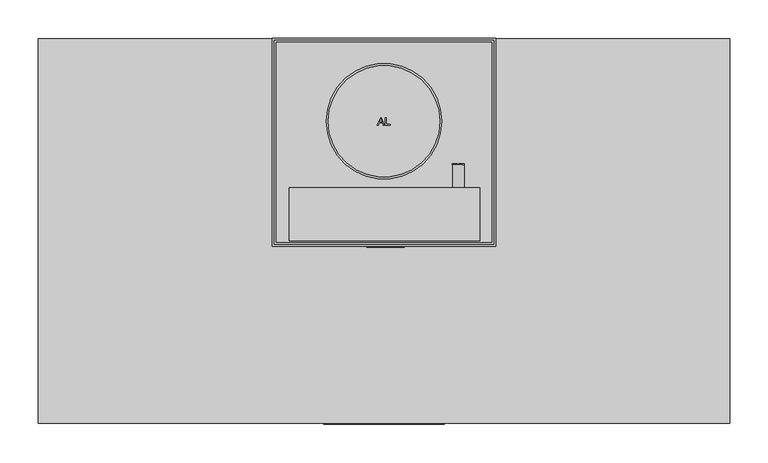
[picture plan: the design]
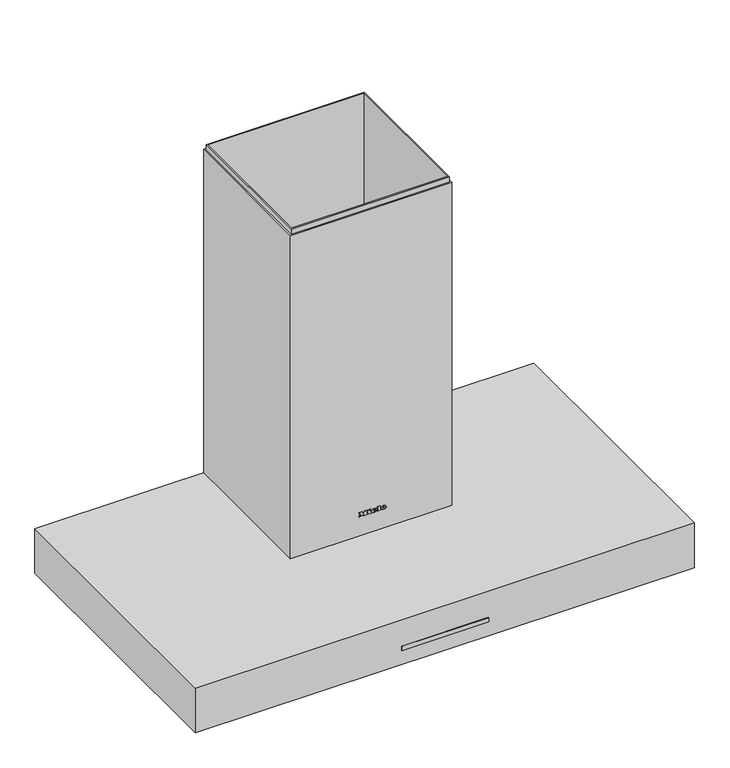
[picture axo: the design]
"""IFC4 building model written with IfcOpenShell, lengths in millimetres: proxy geometry."""

import ifcopenshell
import ifcopenshell.guid

model = None  # the IFC model being written
_history = None  # IfcOwnerHistory: only IFC2X3 demands one
_inside = {}  # id of a spatial element -> (the spatial element, [elements in it])
_under = {}  # id of a project, library or spatial element -> (it, [spatial elements below it])
_declared = {}  # id of a project -> (the project, [libraries it declares])
_typed = {}  # id of a type object -> (the type object, [elements of that type])
_made_of = {}  # id of a material, layer set ... -> (it, [elements and type objects made of it])


def new_model(schema):
    """Start an empty IFC model of exactly this schema.

    Asked for "IFC4X3", IfcOpenShell would pick the latest addendum, in which some entities
    have other attributes; the version numbers below select the first issue.
    IFC2X3 requires an IfcOwnerHistory on every rooted entity: one is made here for all.
    """
    global model, _history
    if schema == "IFC4X3":
        model = ifcopenshell.file(schema_version=(4, 3, 0, 0))
    else:
        model = ifcopenshell.file(schema=schema)
    _inside.clear()
    _under.clear()
    _declared.clear()
    _typed.clear()
    _made_of.clear()
    _history = None
    if model.schema == "IFC2X3":
        org = make("IfcOrganization", Name="unknown")
        user = make(
            "IfcPersonAndOrganization",
            ThePerson=make("IfcPerson", FamilyName="unknown"),
            TheOrganization=org,
        )
        app = make(
            "IfcApplication",
            ApplicationDeveloper=org,
            Version="unknown",
            ApplicationFullName="unknown",
            ApplicationIdentifier="unknown",
        )
        _history = make(
            "IfcOwnerHistory",
            OwningUser=user,
            OwningApplication=app,
            ChangeAction="ADDED",
            CreationDate=0,
        )
    return model


def make(cls, **values):
    """One entity of the class cls with the attributes given. An attribute that is None is left unset."""
    return model.create_entity(
        cls, **{name: value for name, value in values.items() if value is not None}
    )


def rooted(cls, **values):
    """An entity with a GlobalId (a new one), such as an element, a storey or a relation."""
    return make(cls, GlobalId=ifcopenshell.guid.new(), OwnerHistory=_history, **values)


def si_unit(unit_type, name, prefix=None):
    """IfcSIUnit, for example si_unit("LENGTHUNIT", "METRE", prefix="MILLI")."""
    return make("IfcSIUnit", UnitType=unit_type, Prefix=prefix, Name=name)


def assignment(units):
    """IfcUnitAssignment: the units of a project."""
    return None if units is None else make("IfcUnitAssignment", Units=units)


def point(xyz):
    """IfcCartesianPoint."""
    return None if xyz is None else make("IfcCartesianPoint", Coordinates=xyz)


def direction(xyz):
    """IfcDirection."""
    return None if xyz is None else make("IfcDirection", DirectionRatios=xyz)


def frame(location, z_axis=None, x_axis=None):
    """IfcAxis2Placement3D, a coordinate frame: its origin and axes. An axis left out is left unset."""
    return make(
        "IfcAxis2Placement3D",
        Location=point(location),
        Axis=direction(z_axis),
        RefDirection=direction(x_axis),
    )


def frame_2d(location, x_axis=None):
    """IfcAxis2Placement2D, a coordinate frame in the plane: its origin and x axis."""
    return make(
        "IfcAxis2Placement2D", Location=point(location), RefDirection=direction(x_axis)
    )


def origin():
    """The frame at (0, 0, 0) with its axes left unset."""
    return frame((0.0, 0.0, 0.0))


def place(relative_to, where):
    """IfcLocalPlacement: puts the frame where relative to a parent placement (None: the world)."""
    return make(
        "IfcLocalPlacement", PlacementRelTo=relative_to, RelativePlacement=where
    )


def context(
    kind, dimensions, precision=None, world=None, true_north=None, identifier=None
):
    """IfcGeometricRepresentationContext, for example the 3D "Model" context."""
    return make(
        "IfcGeometricRepresentationContext",
        ContextIdentifier=identifier,
        ContextType=kind,
        CoordinateSpaceDimension=dimensions,
        Precision=precision,
        WorldCoordinateSystem=world,
        TrueNorth=true_north,
    )


def project(units=None, contexts=None):
    """IfcProject with its units and contexts."""
    return rooted(
        "IfcProject",
        Name="project",
        RepresentationContexts=contexts,
        UnitsInContext=assignment(units),
    )


def spatial(cls, under=None, at=None, **own):
    """A site, building, storey or space (cls), placed at a placement, below another one or the project."""
    s = rooted(cls, ObjectPlacement=at, **own)
    if under is not None:
        _under.setdefault(under.id(), (under, []))[1].append(s)
    return s


def polyline(points):
    """IfcPolyline through the points."""
    return make("IfcPolyline", Points=[point(p) for p in points])


def circle_curve(where, radius):
    """IfcCircle in the frame where."""
    return make("IfcCircle", Position=where, Radius=radius)


def ellipse_curve(where, semi_axis1, semi_axis2):
    """IfcEllipse in the frame where."""
    return make(
        "IfcEllipse", Position=where, SemiAxis1=semi_axis1, SemiAxis2=semi_axis2
    )


def trimmed(basis, trim1, trim2, sense, master):
    """IfcTrimmedCurve: the piece of a basis curve between two trims."""
    return make(
        "IfcTrimmedCurve",
        BasisCurve=basis,
        Trim1=trim1,
        Trim2=trim2,
        SenseAgreement=sense,
        MasterRepresentation=master,
    )


def segment(curve, same_sense, transition):
    """IfcCompositeCurveSegment."""
    return make(
        "IfcCompositeCurveSegment",
        Transition=transition,
        SameSense=same_sense,
        ParentCurve=curve,
    )


def composite_curve(segments, self_intersect=None):
    """IfcCompositeCurve: segments joined end to end."""
    return make("IfcCompositeCurve", Segments=segments, SelfIntersect=self_intersect)


def outline(outer, holes=None, kind="AREA"):
    """IfcArbitraryClosedProfileDef: a profile drawn as a closed curve; with holes, ...WithVoids."""
    if holes is None:
        return make("IfcArbitraryClosedProfileDef", ProfileType=kind, OuterCurve=outer)
    return make(
        "IfcArbitraryProfileDefWithVoids",
        ProfileType=kind,
        OuterCurve=outer,
        InnerCurves=holes,
    )


def extrude(swept, where, along, depth):
    """IfcExtrudedAreaSolid: the profile swept, set in the frame where, extruded along a direction by depth."""
    return make(
        "IfcExtrudedAreaSolid",
        SweptArea=swept,
        Position=where,
        ExtrudedDirection=direction(along),
        Depth=depth,
    )


def faces_of(points, faces, orient=None, outer=None):
    """IfcFace entities. A face is a list of loops; a loop is a list of indices into points, from 0.

    orient and outer hold one flag for each loop. By default every Orientation is true, the
    first loop of a face is its IfcFaceOuterBound and the others are IfcFaceBound.
    """
    made = []
    for i, loops in enumerate(faces):
        bounds = []
        for j, loop in enumerate(loops):
            is_outer = j == 0 if outer is None else outer[i][j]
            bounds.append(
                make(
                    "IfcFaceOuterBound" if is_outer else "IfcFaceBound",
                    Bound=make("IfcPolyLoop", Polygon=[points[k] for k in loop]),
                    Orientation=True if orient is None else orient[i][j],
                )
            )
        made.append(make("IfcFace", Bounds=bounds))
    return made


def faceted_brep(points, faces, orient=None, outer=None, voids=None):
    """IfcFacetedBrep: a solid bounded by flat faces; with voids (closed shells), ...WithVoids."""
    shared = [point(p) for p in points]
    hull = make("IfcClosedShell", CfsFaces=faces_of(shared, faces, orient, outer))
    if voids is None:
        return make("IfcFacetedBrep", Outer=hull)
    return make(
        "IfcFacetedBrepWithVoids",
        Outer=hull,
        Voids=[
            make(cls, CfsFaces=faces_of(shared, fs, o, b)) for cls, fs, o, b in voids
        ],
    )


def shape(context_of_items, identifier, shape_type, items):
    """IfcShapeRepresentation: the items that make up one representation, for example the "Body"."""
    return make(
        "IfcShapeRepresentation",
        ContextOfItems=context_of_items,
        RepresentationIdentifier=identifier,
        RepresentationType=shape_type,
        Items=items,
    )


def source(mapping_origin, context_of_items, identifier, shape_type, items):
    """IfcRepresentationMap: a shape defined once, which mapped items show again and again."""
    return make(
        "IfcRepresentationMap",
        MappingOrigin=mapping_origin,
        MappedRepresentation=shape(context_of_items, identifier, shape_type, items),
    )


def transform(
    local_origin,
    x_axis=None,
    y_axis=None,
    z_axis=None,
    scale=None,
    scale2=None,
    scale3=None,
    uniform=True,
):
    """IfcCartesianTransformationOperator3D, or its non-uniform kind. x_axis, y_axis, z_axis: its Axis1, 2, 3."""
    if uniform:
        return make(
            "IfcCartesianTransformationOperator3D",
            Axis1=direction(x_axis),
            Axis2=direction(y_axis),
            LocalOrigin=point(local_origin),
            Scale=scale,
            Axis3=direction(z_axis),
        )
    return make(
        "IfcCartesianTransformationOperator3DnonUniform",
        Axis1=direction(x_axis),
        Axis2=direction(y_axis),
        LocalOrigin=point(local_origin),
        Scale=scale,
        Axis3=direction(z_axis),
        Scale2=scale2,
        Scale3=scale3,
    )


def mapped(mapping_source, mapping_target):
    """IfcMappedItem: shows the shape of a source again, moved by a transform."""
    return make(
        "IfcMappedItem", MappingSource=mapping_source, MappingTarget=mapping_target
    )


def made_of(thing, what):
    """Note that an element or type object is made of a material, layer set ...; save() writes the relation."""
    if what is not None:
        _made_of.setdefault(what.id(), (what, []))[1].append(thing)
    return thing


def element(
    cls,
    number,
    at=None,
    inside=None,
    cuts=None,
    type_object=None,
    material=None,
    context=None,
    identifier="Body",
    shape_type=None,
    held_by="IfcProductDefinitionShape",
    body=None,
    shapes=None,
    **own,
):
    """One element of the class cls, such as IfcWall. Its Tag is "e" and its number.

    at: its placement. inside: the storey or other place that contains it. cuts: it is an
    opening in that element (IfcRelVoidsElement). A single representation is given by context,
    identifier, shape_type and body (its items); several are given by shapes. held_by: the class
    of the entity that holds the representations. save() writes the other relations.
    """
    e = rooted(cls, Tag="e%d" % number, ObjectPlacement=at, **own)
    if body is not None:
        shapes = [shape(context, identifier, shape_type, body)]
    if shapes is not None:
        e.Representation = make(held_by, Representations=shapes)
    if inside is not None:
        _inside.setdefault(inside.id(), (inside, []))[1].append(e)
    if cuts is not None:
        rooted(
            "IfcRelVoidsElement", RelatingBuildingElement=cuts, RelatedOpeningElement=e
        )
    if type_object is not None:
        _typed.setdefault(type_object.id(), (type_object, []))[1].append(e)
    return made_of(e, material)


def aggregate(whole, parts):
    """IfcRelAggregates: a whole, such as a stair, and the parts it consists of."""
    return rooted("IfcRelAggregates", RelatingObject=whole, RelatedObjects=parts)


def save(model, path):
    """Write the relations noted so far, then the file.

    IfcRelAggregates (storeys below a building ...), IfcRelContainedInSpatialStructure (elements
    in a storey), IfcRelDefinesByType, IfcRelAssociatesMaterial and IfcRelDeclares: one each for
    every whole, place, type object, material and project.
    """
    for whole, parts in _under.values():
        aggregate(whole, parts)
    for where, things in _inside.values():
        rooted(
            "IfcRelContainedInSpatialStructure",
            RelatedElements=things,
            RelatingStructure=where,
        )
    for kind, things in _typed.values():
        rooted("IfcRelDefinesByType", RelatedObjects=things, RelatingType=kind)
    for what, things in _made_of.values():
        rooted("IfcRelAssociatesMaterial", RelatedObjects=things, RelatingMaterial=what)
    for by, libraries in _declared.values():
        rooted("IfcRelDeclares", RelatingContext=by, RelatedDefinitions=libraries)
    model.write(path)


def plane_surface(at):
    """IfcPlane: the flat surface through the origin of the frame at, square to its z axis."""
    return make("IfcPlane", Position=at)


def cylinder_surface(at, radius):
    """IfcCylindricalSurface: all points at the distance radius from the z axis of the frame at."""
    return make("IfcCylindricalSurface", Position=at, Radius=radius)


def revolved_surface(curve, axis_point, axis_direction):
    """IfcSurfaceOfRevolution: the curve turned about the line through axis_point along axis_direction."""
    return make(
        "IfcSurfaceOfRevolution",
        SweptCurve=make("IfcArbitraryOpenProfileDef", ProfileType="CURVE", Curve=curve),
        AxisPosition=make("IfcAxis1Placement", Location=point(axis_point), Axis=direction(axis_direction)),
    )


def extruded_surface(curve, direction_of_extrusion, depth):
    """IfcSurfaceOfLinearExtrusion: the curve pushed along a direction by depth."""
    return make(
        "IfcSurfaceOfLinearExtrusion",
        SweptCurve=make("IfcArbitraryOpenProfileDef", ProfileType="CURVE", Curve=curve),
        ExtrudedDirection=direction(direction_of_extrusion),
        Depth=depth,
    )


def advanced_brep(points, edges, surfaces, faces):
    """IfcAdvancedBrep: a solid bounded by faces that lie on surfaces and meet in shared edges.

    An edge is (start, end): straight between two places in points (the first is 0);
    or (start, end, curve); or (start, end, curve, False) where it runs against its curve.
    A face is (place in surfaces, loops), or (place, loops, False) where it looks against
    its surface's normal. A loop lists edges by number (the first is 1), with a minus sign
    where the edge is run from its end to its start. The first loop is the outer one.
    """
    corners = [point(p) for p in points]
    vertices = [make("IfcVertexPoint", VertexGeometry=c) for c in corners]
    made = []
    for start, end, *more in edges:
        made.append(
            make(
                "IfcEdgeCurve",
                EdgeStart=vertices[start],
                EdgeEnd=vertices[end],
                EdgeGeometry=more[0] if more else make("IfcPolyline", Points=[corners[start], corners[end]]),
                SameSense=more[1] if len(more) > 1 else True,
            )
        )
    hull = []
    for where, loops, *sense in faces:
        bounds = []
        for j, loop in enumerate(loops):
            ring = [make("IfcOrientedEdge", EdgeElement=made[abs(k) - 1], Orientation=k > 0) for k in loop]
            bounds.append(
                make(
                    "IfcFaceOuterBound" if j == 0 else "IfcFaceBound",
                    Bound=make("IfcEdgeLoop", EdgeList=ring),
                    Orientation=True,
                )
            )
        hull.append(make("IfcAdvancedFace", Bounds=bounds, FaceSurface=surfaces[where], SameSense=sense[0] if sense else True))
    return make("IfcAdvancedBrep", Outer=make("IfcClosedShell", CfsFaces=hull))


def specialty_equipment_d0c3b859(model_context):
    return source(origin(), model_context, "Body", "SolidModel", [
        advanced_brep(
        [(-270.0, -20.971114, 2.6236572), (-270.0, -76.028886, 17.3763428), (-270.0, -48.5, 10.0), (-270.0, -22.9370789, 1.9081045), (-270.0, -74.6840869, 15.7736735), (-270.0, -48.8105829, 8.840889)],
        [
            (0, 1, circle_curve(frame((-270.0, -48.5, 10.0), z_axis=(0.0, 0.25881904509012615, 0.9659258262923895), x_axis=(0.0, -0.9659258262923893, 0.2588190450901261)), 28.5)),
            (1, 2),
            (2, 0),
            (1, 0, circle_curve(frame((-270.0, -48.5, 10.0), z_axis=(0.0, 0.25881904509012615, 0.9659258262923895), x_axis=(0.0, -0.9659258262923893, 0.2588190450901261)), 28.5)),
            (0, 3),
            (3, 4, circle_curve(frame((-270.0, -48.8105829, 8.840889), z_axis=(0.0, 0.25881904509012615, 0.9659258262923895), x_axis=(0.0, -0.9659258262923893, 0.2588190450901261)), 26.7862224)),
            (4, 1),
            (4, 3, circle_curve(frame((-270.0, -48.8105829, 8.840889), z_axis=(0.0, 0.25881904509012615, 0.9659258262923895), x_axis=(0.0, -0.9659258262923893, 0.2588190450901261)), 26.7862224)),
            (3, 5),
            (5, 4),
        ],
        [
            plane_surface(frame((-270.0, -48.5, 10.0), z_axis=(0.0, 0.25881904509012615, 0.9659258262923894), x_axis=(0.0, -0.9659258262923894, 0.25881904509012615))),
            revolved_surface(polyline([(-270.0, -76.028886, 17.3763428), (-270.0, -74.6840869, 15.7736735)]), (-270.0, -48.5, 10.0), (0.0, -0.2588190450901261, -0.9659258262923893)),
            plane_surface(frame((-270.0, -48.8105829, 8.840889), z_axis=(0.0, -0.25881904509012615, -0.9659258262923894), x_axis=(0.0, -0.9659258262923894, 0.25881904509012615))),
        ],
        [
            (0, [[1, 2, 3]]),
            (0, [[-2, 4, -3]]),
            (1, [[-1, 5, 6, 7]]),
            (1, [[-4, -7, 8, -5]]),
            (2, [[-6, 9, 10]]),
            (2, [[-8, -10, -9]]),
        ],
    ),
        advanced_brep(
        [(0.0, -20.971114, 2.6236572), (0.0, -76.028886, 17.3763428), (0.0, -48.5, 10.0), (0.0, -22.9370789, 1.9081045), (0.0, -74.6840869, 15.7736735), (0.0, -48.8105829, 8.840889)],
        [
            (0, 1, circle_curve(frame((0.0, -48.5, 10.0), z_axis=(0.0, 0.2588190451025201, 0.9659258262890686), x_axis=(0.0, -0.9659258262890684, 0.25881904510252)), 28.5)),
            (1, 2),
            (2, 0),
            (1, 0, circle_curve(frame((0.0, -48.5, 10.0), z_axis=(0.0, 0.2588190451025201, 0.9659258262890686), x_axis=(0.0, -0.9659258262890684, 0.25881904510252)), 28.5)),
            (0, 3),
            (3, 4, circle_curve(frame((0.0, -48.8105829, 8.840889), z_axis=(0.0, 0.2588190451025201, 0.9659258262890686), x_axis=(0.0, -0.9659258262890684, 0.25881904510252)), 26.7862224)),
            (4, 1),
            (4, 3, circle_curve(frame((0.0, -48.8105829, 8.840889), z_axis=(0.0, 0.2588190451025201, 0.9659258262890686), x_axis=(0.0, -0.9659258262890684, 0.25881904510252)), 26.7862224)),
            (3, 5),
            (5, 4),
        ],
        [
            plane_surface(frame((0.0, -48.5, 10.0), z_axis=(0.0, 0.2588190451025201, 0.9659258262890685), x_axis=(0.0, -0.9659258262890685, 0.2588190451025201))),
            revolved_surface(polyline([(0.0, -76.028886, 17.3763428), (0.0, -74.6840869, 15.7736735)]), (0.0, -48.5, 10.0), (0.0, -0.25881904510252, -0.9659258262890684)),
            plane_surface(frame((0.0, -48.8105829, 8.840889), z_axis=(0.0, -0.2588190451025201, -0.9659258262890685), x_axis=(0.0, -0.9659258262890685, 0.2588190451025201))),
        ],
        [
            (0, [[1, 2, 3]]),
            (0, [[-2, 4, -3]]),
            (1, [[-1, 5, 6, 7]]),
            (1, [[-4, -7, 8, -5]]),
            (2, [[-6, 9, 10]]),
            (2, [[-8, -10, -9]]),
        ],
    ),
        advanced_brep(
        [(270.0, -20.971114, 2.6236572), (270.0, -76.028886, 17.3763428), (270.0, -48.5, 10.0), (270.0, -22.9370789, 1.9081045), (270.0, -74.6840869, 15.7736735), (270.0, -48.8105829, 8.840889)],
        [
            (0, 1, circle_curve(frame((270.0, -48.5, 10.0), z_axis=(0.0, 0.2588190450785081, 0.9659258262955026), x_axis=(0.0, -0.9659258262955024, 0.25881904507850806)), 28.5)),
            (1, 2),
            (2, 0),
            (1, 0, circle_curve(frame((270.0, -48.5, 10.0), z_axis=(0.0, 0.2588190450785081, 0.9659258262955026), x_axis=(0.0, -0.9659258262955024, 0.25881904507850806)), 28.5)),
            (0, 3),
            (3, 4, circle_curve(frame((270.0, -48.8105829, 8.840889), z_axis=(0.0, 0.2588190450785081, 0.9659258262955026), x_axis=(0.0, -0.9659258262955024, 0.25881904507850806)), 26.7862224)),
            (4, 1),
            (4, 3, circle_curve(frame((270.0, -48.8105829, 8.840889), z_axis=(0.0, 0.2588190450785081, 0.9659258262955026), x_axis=(0.0, -0.9659258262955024, 0.25881904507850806)), 26.7862224)),
            (3, 5),
            (5, 4),
        ],
        [
            plane_surface(frame((270.0, -48.5, 10.0), z_axis=(0.0, 0.2588190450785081, 0.9659258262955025), x_axis=(0.0, -0.9659258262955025, 0.2588190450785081))),
            revolved_surface(polyline([(270.0, -76.028886, 17.3763428), (270.0, -74.6840869, 15.7736735)]), (270.0, -48.5, 10.0), (0.0, -0.25881904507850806, -0.9659258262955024)),
            plane_surface(frame((270.0, -48.8105829, 8.840889), z_axis=(0.0, -0.2588190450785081, -0.9659258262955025), x_axis=(0.0, -0.9659258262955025, 0.2588190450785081))),
        ],
        [
            (0, [[1, 2, 3]]),
            (0, [[-2, 4, -3]]),
            (1, [[-1, 5, 6, 7]]),
            (1, [[-4, -7, 8, -5]]),
            (2, [[-6, 9, 10]]),
            (2, [[-8, -10, -9]]),
        ],
    ),
        extrude(outline(polyline([(131.6666667, -106.0), (131.6666667, -464.0), (-131.6666667, -464.0), (-131.6666667, -106.0), (131.6666667, -106.0)])), frame((0.0, 0.0, 6.5), z_axis=(0.0, 0.0, 1.0), x_axis=(1.0, 0.0, 0.0)), (0.0, 0.0, 1.0), 6.0),
        extrude(outline(polyline([(140.6666667, -97.0), (140.6666667, -473.0), (-140.6666667, -473.0), (-140.6666667, -97.0), (140.6666667, -97.0)]), holes=[polyline([(131.6666667, -106.0), (-131.6666667, -106.0), (-131.6666667, -464.0), (131.6666667, -464.0), (131.6666667, -106.0)])]), frame((0.0, 0.0, 5.0), z_axis=(0.0, 0.0, 1.0), x_axis=(1.0, 0.0, 0.0)), (0.0, 0.0, 1.0), 9.0),
        extrude(outline(polyline([(149.6666667, -106.0), (413.0, -106.0), (413.0, -464.0), (149.6666667, -464.0), (149.6666667, -106.0)])), frame((0.0, 0.0, 6.5), z_axis=(0.0, 0.0, 1.0), x_axis=(1.0, 0.0, 0.0)), (0.0, 0.0, 1.0), 6.0),
        extrude(outline(polyline([(140.6666667, -97.0), (422.0, -97.0), (422.0, -473.0), (140.6666667, -473.0), (140.6666667, -97.0)]), holes=[polyline([(149.6666667, -106.0), (149.6666667, -464.0), (413.0, -464.0), (413.0, -106.0), (149.6666667, -106.0)])]), frame((0.0, 0.0, 5.0), z_axis=(0.0, 0.0, 1.0), x_axis=(1.0, 0.0, 0.0)), (0.0, 0.0, 1.0), 9.0),
        extrude(outline(polyline([(-149.6666667, -106.0), (-149.6666667, -464.0), (-413.0, -464.0), (-413.0, -106.0), (-149.6666667, -106.0)])), frame((0.0, 0.0, 6.5), z_axis=(0.0, 0.0, 1.0), x_axis=(1.0, 0.0, 0.0)), (0.0, 0.0, 1.0), 6.0),
        extrude(outline(polyline([(-140.6666667, -97.0), (-140.6666667, -473.0), (-422.0, -473.0), (-422.0, -97.0), (-140.6666667, -97.0)]), holes=[polyline([(-149.6666667, -106.0), (-413.0, -106.0), (-413.0, -464.0), (-149.6666667, -464.0), (-149.6666667, -106.0)])]), frame((0.0, 0.0, 5.0), z_axis=(0.0, 0.0, 1.0), x_axis=(1.0, 0.0, 0.0)), (0.0, 0.0, 1.0), 9.0),
        extrude(outline(polyline([(16.5, -421.0), (16.5, -464.0), (-16.5, -464.0), (-16.5, -421.0), (16.5, -421.0)]), holes=[polyline([(10.0, -427.5), (-10.0, -427.5), (-10.0, -436.5), (10.0, -436.5), (10.0, -427.5)])]), frame((0.0, 0.0, 5.0), z_axis=(0.0, 0.0, 1.0), x_axis=(1.0, 0.0, 0.0)), (0.0, 0.0, 1.0), 1.5),
        extrude(outline(polyline([(264.8333333, -421.0), (297.8333333, -421.0), (297.8333333, -464.0), (264.8333333, -464.0), (264.8333333, -421.0)]), holes=[polyline([(271.3333333, -427.5), (271.3333333, -436.5), (291.1047662, -436.5), (291.1047662, -427.5), (271.3333333, -427.5)])]), frame((0.0, 0.0, 5.0), z_axis=(0.0, 0.0, 1.0), x_axis=(1.0, 0.0, 0.0)), (0.0, 0.0, 1.0), 1.5),
        extrude(outline(polyline([(-264.8333333, -421.0), (-264.8333333, -464.0), (-297.8333333, -464.0), (-297.8333333, -421.0), (-264.8333333, -421.0)]), holes=[polyline([(-271.3333333, -427.5), (-291.3333333, -427.5), (-291.3333333, -436.5), (-271.3333333, -436.5), (-271.3333333, -427.5)])]), frame((0.0, 0.0, 5.0), z_axis=(0.0, 0.0, 1.0), x_axis=(1.0, 0.0, 0.0)), (0.0, 0.0, 1.0), 1.5),
        faceted_brep([(140.0, -5.0, 710.0), (-140.0, -5.0, 710.0), (-140.0, -5.0, 235.0), (140.0, -5.0, 235.0), (-140.0, -265.0, 710.0), (140.0, -265.0, 710.0), (140.0, -265.0, 235.0), (-140.0, -265.0, 235.0), (121.0, -265.0, 270.0), (121.0, -265.0, 370.0), (109.0, -265.0, 370.0), (109.0, -265.0, 270.0), (-121.0, -265.0, 370.0), (-121.0, -265.0, 270.0), (-109.0, -265.0, 270.0), (-109.0, -265.0, 370.0), (-86.0, -265.0, 370.0), (-97.5, -265.0, 370.0), (-97.5, -265.0, 270.0), (-86.0, -265.0, 270.0), (-63.0, -265.0, 370.0), (-74.5, -265.0, 370.0), (-74.5, -265.0, 270.0), (-63.0, -265.0, 270.0), (-40.0, -265.0, 370.0), (-51.5, -265.0, 370.0), (-51.5, -265.0, 270.0), (-40.0, -265.0, 270.0), (-17.0, -265.0, 370.0), (-28.5, -265.0, 370.0), (-28.5, -265.0, 270.0), (-17.0, -265.0, 270.0), (5.5, -265.0, 370.0), (-5.5, -265.0, 370.0), (-5.5, -265.0, 270.0), (5.5, -265.0, 270.0), (28.5, -265.0, 370.0), (17.0, -265.0, 370.0), (17.0, -265.0, 270.0), (28.5, -265.0, 270.0), (51.5, -265.0, 370.0), (40.0, -265.0, 370.0), (40.0, -265.0, 270.0), (51.5, -265.0, 270.0), (74.5, -265.0, 370.0), (63.0, -265.0, 370.0), (63.0, -265.0, 270.0), (74.5, -265.0, 270.0), (97.5, -265.0, 370.0), (86.0, -265.0, 370.0), (86.0, -265.0, 270.0), (97.5, -265.0, 270.0), (-142.5, -65.4, 270.0), (-140.0, -65.4, 270.0), (-140.0, -65.4, 370.0), (-142.5, -65.4, 370.0), (-140.0, -76.0, 370.0), (-142.5, -76.0, 370.0), (-140.0, -44.2, 270.0), (-142.5, -44.2, 270.0), (-142.5, -54.8, 270.0), (-140.0, -54.8, 270.0), (-140.0, -44.2, 370.0), (-142.5, -44.2, 370.0), (-140.0, -23.0, 270.0), (-142.5, -23.0, 270.0), (-142.5, -33.6, 270.0), (-140.0, -33.6, 270.0), (-140.0, -23.0, 370.0), (-142.5, -23.0, 370.0), (-121.0, -267.5, 370.0), (-109.0, -267.5, 370.0), (-109.0, -267.5, 270.0), (-86.0, -267.5, 370.0), (-97.5, -267.5, 370.0), (-63.0, -267.5, 370.0), (-74.5, -267.5, 370.0), (-40.0, -267.5, 370.0), (-51.5, -267.5, 370.0), (-17.0, -267.5, 370.0), (-28.5, -267.5, 370.0), (5.5, -267.5, 370.0), (-5.5, -267.5, 370.0), (28.5, -267.5, 370.0), (17.0, -267.5, 370.0), (51.5, -267.5, 370.0), (40.0, -267.5, 370.0), (74.5, -267.5, 370.0), (63.0, -267.5, 370.0), (97.5, -267.5, 370.0), (86.0, -267.5, 370.0), (-142.5, -267.5, 710.0), (142.5, -267.5, 710.0), (142.5, -2.5, 710.0), (-142.5, -2.5, 710.0), (-142.5, -267.5, 235.0), (-142.5, -2.5, 235.0), (142.5, -2.5, 235.0), (142.5, -267.5, 235.0), (-142.5, -247.0, 270.0), (-142.5, -236.4, 270.0), (-142.5, -236.4, 370.0), (-142.5, -247.0, 370.0), (-142.5, -225.8, 270.0), (-142.5, -215.2, 270.0), (-142.5, -215.2, 370.0), (-142.5, -225.8, 370.0), (-142.5, -204.6, 270.0), (-142.5, -194.0, 270.0), (-142.5, -194.0, 370.0), (-142.5, -204.6, 370.0), (-142.5, -183.4, 270.0), (-142.5, -172.8, 270.0), (-142.5, -172.8, 370.0), (-142.5, -183.4, 370.0), (-142.5, -162.2, 270.0), (-142.5, -151.6, 270.0), (-142.5, -151.6, 370.0), (-142.5, -162.2, 370.0), (-142.5, -141.0, 270.0), (-142.5, -129.0, 270.0), (-142.5, -129.0, 370.0), (-142.5, -141.0, 370.0), (-142.5, -118.4, 270.0), (-142.5, -107.8, 270.0), (-142.5, -107.8, 370.0), (-142.5, -118.4, 370.0), (-142.5, -97.2, 270.0), (-142.5, -86.6, 270.0), (-142.5, -86.6, 370.0), (-142.5, -97.2, 370.0), (-142.5, -76.0, 270.0), (-142.5, -54.8, 370.0), (-142.5, -33.6, 370.0), (-140.0, -236.4, 270.0), (-140.0, -247.0, 270.0), (-140.0, -247.0, 370.0), (-140.0, -236.4, 370.0), (-140.0, -215.2, 270.0), (-140.0, -225.8, 270.0), (-140.0, -225.8, 370.0), (-140.0, -215.2, 370.0), (-140.0, -194.0, 270.0), (-140.0, -204.6, 270.0), (-140.0, -204.6, 370.0), (-140.0, -194.0, 370.0), (-140.0, -172.8, 270.0), (-140.0, -183.4, 270.0), (-140.0, -183.4, 370.0), (-140.0, -172.8, 370.0), (-140.0, -151.6, 270.0), (-140.0, -162.2, 270.0), (-140.0, -162.2, 370.0), (-140.0, -151.6, 370.0), (-140.0, -129.0, 270.0), (-140.0, -141.0, 270.0), (-140.0, -141.0, 370.0), (-140.0, -129.0, 370.0), (-140.0, -107.8, 270.0), (-140.0, -118.4, 270.0), (-140.0, -118.4, 370.0), (-140.0, -107.8, 370.0), (-140.0, -86.6, 270.0), (-140.0, -97.2, 270.0), (-140.0, -97.2, 370.0), (-140.0, -86.6, 370.0), (-140.0, -76.0, 270.0), (-140.0, -54.8, 370.0), (-140.0, -33.6, 370.0), (140.0, -162.2, 370.0), (140.0, -162.2, 270.0), (140.0, -151.6, 270.0), (140.0, -151.6, 370.0), (140.0, -44.2, 270.0), (140.0, -44.2, 370.0), (140.0, -54.8, 370.0), (140.0, -54.8, 270.0), (140.0, -65.4, 270.0), (140.0, -65.4, 370.0), (140.0, -76.0, 370.0), (140.0, -76.0, 270.0), (140.0, -86.6, 270.0), (140.0, -86.6, 370.0), (140.0, -97.2, 370.0), (140.0, -97.2, 270.0), (140.0, -107.8, 270.0), (140.0, -107.8, 370.0), (140.0, -118.4, 370.0), (140.0, -118.4, 270.0), (140.0, -129.0, 270.0), (140.0, -129.0, 370.0), (140.0, -141.0, 370.0), (140.0, -141.0, 270.0), (140.0, -247.0, 370.0), (140.0, -247.0, 270.0), (140.0, -236.4, 270.0), (140.0, -236.4, 370.0), (140.0, -23.0, 270.0), (140.0, -23.0, 370.0), (140.0, -33.6, 370.0), (140.0, -33.6, 270.0), (140.0, -225.8, 370.0), (140.0, -225.8, 270.0), (140.0, -215.2, 270.0), (140.0, -215.2, 370.0), (140.0, -204.6, 370.0), (140.0, -204.6, 270.0), (140.0, -194.0, 270.0), (140.0, -194.0, 370.0), (140.0, -183.4, 370.0), (140.0, -183.4, 270.0), (140.0, -172.8, 270.0), (140.0, -172.8, 370.0), (142.5, -225.8, 270.0), (142.5, -225.8, 370.0), (142.5, -215.2, 370.0), (142.5, -215.2, 270.0), (142.5, -204.6, 270.0), (142.5, -204.6, 370.0), (142.5, -194.0, 370.0), (142.5, -194.0, 270.0), (142.5, -183.4, 270.0), (142.5, -183.4, 370.0), (142.5, -172.8, 370.0), (142.5, -172.8, 270.0), (142.5, -162.2, 270.0), (142.5, -162.2, 370.0), (142.5, -151.6, 370.0), (142.5, -151.6, 270.0), (142.5, -44.2, 370.0), (142.5, -44.2, 270.0), (142.5, -54.8, 270.0), (142.5, -54.8, 370.0), (142.5, -65.4, 370.0), (142.5, -65.4, 270.0), (142.5, -76.0, 270.0), (142.5, -76.0, 370.0), (142.5, -86.6, 370.0), (142.5, -86.6, 270.0), (142.5, -97.2, 270.0), (142.5, -97.2, 370.0), (142.5, -107.8, 370.0), (142.5, -107.8, 270.0), (142.5, -118.4, 270.0), (142.5, -118.4, 370.0), (142.5, -129.0, 370.0), (142.5, -129.0, 270.0), (142.5, -141.0, 270.0), (142.5, -141.0, 370.0), (142.5, -23.0, 370.0), (142.5, -23.0, 270.0), (142.5, -33.6, 270.0), (142.5, -33.6, 370.0), (142.5, -247.0, 270.0), (142.5, -247.0, 370.0), (142.5, -236.4, 370.0), (142.5, -236.4, 270.0), (-86.0, -267.5, 270.0), (-97.5, -267.5, 270.0), (-63.0, -267.5, 270.0), (-74.5, -267.5, 270.0), (-40.0, -267.5, 270.0), (-51.5, -267.5, 270.0), (-17.0, -267.5, 270.0), (-28.5, -267.5, 270.0), (5.5, -267.5, 270.0), (-5.5, -267.5, 270.0), (28.5, -267.5, 270.0), (17.0, -267.5, 270.0), (51.5, -267.5, 270.0), (40.0, -267.5, 270.0), (74.5, -267.5, 270.0), (63.0, -267.5, 270.0), (97.5, -267.5, 270.0), (86.0, -267.5, 270.0), (121.0, -267.5, 370.0), (121.0, -267.5, 270.0), (109.0, -267.5, 270.0), (109.0, -267.5, 370.0), (-121.0, -267.5, 270.0)], [[[0, 1, 2, 3]], [[4, 5, 6, 7], [8, 9, 10, 11], [12, 13, 14, 15], [16, 17, 18, 19], [20, 21, 22, 23], [24, 25, 26, 27], [28, 29, 30, 31], [32, 33, 34, 35], [36, 37, 38, 39], [40, 41, 42, 43], [44, 45, 46, 47], [48, 49, 50, 51]], [[52, 53, 54, 55]], [[55, 54, 56, 57]], [[58, 59, 60, 61]], [[59, 58, 62, 63]], [[64, 65, 66, 67]], [[65, 64, 68, 69]], [[70, 12, 15, 71]], [[71, 15, 14, 72]], [[16, 73, 74, 17]], [[20, 75, 76, 21]], [[24, 77, 78, 25]], [[28, 79, 80, 29]], [[32, 81, 82, 33]], [[36, 83, 84, 37]], [[40, 85, 86, 41]], [[44, 87, 88, 45]], [[48, 89, 90, 49]], [[91, 92, 93, 94], [0, 5, 4, 1]], [[95, 96, 97, 98], [3, 2, 7, 6]], [[91, 94, 96, 95], [99, 100, 101, 102], [103, 104, 105, 106], [107, 108, 109, 110], [111, 112, 113, 114], [115, 116, 117, 118], [119, 120, 121, 122], [123, 124, 125, 126], [127, 128, 129, 130], [131, 52, 55, 57], [60, 59, 63, 132], [66, 65, 69, 133]], [[1, 4, 7, 2], [134, 135, 136, 137], [138, 139, 140, 141], [142, 143, 144, 145], [146, 147, 148, 149], [150, 151, 152, 153], [154, 155, 156, 157], [158, 159, 160, 161], [162, 163, 164, 165], [53, 166, 56, 54], [58, 61, 167, 62], [64, 67, 168, 68]], [[5, 0, 3, 6], [169, 170, 171, 172], [173, 174, 175, 176], [177, 178, 179, 180], [181, 182, 183, 184], [185, 186, 187, 188], [189, 190, 191, 192], [193, 194, 195, 196], [197, 198, 199, 200], [201, 202, 203, 204], [205, 206, 207, 208], [209, 210, 211, 212]], [[93, 92, 98, 97], [213, 214, 215, 216], [217, 218, 219, 220], [221, 222, 223, 224], [225, 226, 227, 228], [229, 230, 231, 232], [233, 234, 235, 236], [237, 238, 239, 240], [241, 242, 243, 244], [245, 246, 247, 248], [249, 250, 251, 252], [253, 254, 255, 256]], [[92, 91, 95, 98], [74, 73, 257, 258], [76, 75, 259, 260], [78, 77, 261, 262], [80, 79, 263, 264], [82, 81, 265, 266], [84, 83, 267, 268], [86, 85, 269, 270], [88, 87, 271, 272], [90, 89, 273, 274], [275, 276, 277, 278], [279, 70, 71, 72]], [[94, 93, 97, 96]], [[8, 276, 275, 9]], [[12, 70, 279, 13]], [[253, 194, 193, 254]], [[249, 198, 197, 250]], [[194, 253, 256, 195]], [[195, 256, 255, 196]], [[254, 193, 196, 255]], [[198, 249, 252, 199]], [[199, 252, 251, 200]], [[250, 197, 200, 251]], [[213, 202, 201, 214]], [[202, 213, 216, 203]], [[203, 216, 215, 204]], [[214, 201, 204, 215]], [[217, 206, 205, 218]], [[206, 217, 220, 207]], [[207, 220, 219, 208]], [[218, 205, 208, 219]], [[221, 210, 209, 222]], [[210, 221, 224, 211]], [[211, 224, 223, 212]], [[222, 209, 212, 223]], [[225, 170, 169, 226]], [[170, 225, 228, 171]], [[171, 228, 227, 172]], [[226, 169, 172, 227]], [[229, 174, 173, 230]], [[174, 229, 232, 175]], [[175, 232, 231, 176]], [[230, 173, 176, 231]], [[233, 178, 177, 234]], [[178, 233, 236, 179]], [[179, 236, 235, 180]], [[234, 177, 180, 235]], [[237, 182, 181, 238]], [[182, 237, 240, 183]], [[183, 240, 239, 184]], [[238, 181, 184, 239]], [[241, 186, 185, 242]], [[186, 241, 244, 187]], [[187, 244, 243, 188]], [[242, 185, 188, 243]], [[245, 190, 189, 246]], [[190, 245, 248, 191]], [[191, 248, 247, 192]], [[246, 189, 192, 247]], [[134, 100, 99, 135]], [[100, 134, 137, 101]], [[101, 137, 136, 102]], [[135, 99, 102, 136]], [[138, 104, 103, 139]], [[104, 138, 141, 105]], [[105, 141, 140, 106]], [[139, 103, 106, 140]], [[142, 108, 107, 143]], [[108, 142, 145, 109]], [[109, 145, 144, 110]], [[143, 107, 110, 144]], [[146, 112, 111, 147]], [[112, 146, 149, 113]], [[113, 149, 148, 114]], [[147, 111, 114, 148]], [[150, 116, 115, 151]], [[116, 150, 153, 117]], [[117, 153, 152, 118]], [[151, 115, 118, 152]], [[154, 120, 119, 155]], [[120, 154, 157, 121]], [[121, 157, 156, 122]], [[155, 119, 122, 156]], [[158, 124, 123, 159]], [[124, 158, 161, 125]], [[125, 161, 160, 126]], [[159, 123, 126, 160]], [[162, 128, 127, 163]], [[128, 162, 165, 129]], [[129, 165, 164, 130]], [[163, 127, 130, 164]], [[53, 52, 131, 166]], [[166, 131, 57, 56]], [[63, 62, 167, 132]], [[61, 60, 132, 167]], [[69, 68, 168, 133]], [[67, 66, 133, 168]], [[13, 279, 72, 14]], [[276, 8, 11, 277]], [[277, 11, 10, 278]], [[9, 275, 278, 10]], [[73, 16, 19, 257]], [[257, 19, 18, 258]], [[17, 74, 258, 18]], [[75, 20, 23, 259]], [[259, 23, 22, 260]], [[21, 76, 260, 22]], [[77, 24, 27, 261]], [[261, 27, 26, 262]], [[25, 78, 262, 26]], [[79, 28, 31, 263]], [[263, 31, 30, 264]], [[29, 80, 264, 30]], [[81, 32, 35, 265]], [[265, 35, 34, 266]], [[33, 82, 266, 34]], [[83, 36, 39, 267]], [[267, 39, 38, 268]], [[37, 84, 268, 38]], [[85, 40, 43, 269]], [[269, 43, 42, 270]], [[41, 86, 270, 42]], [[87, 44, 47, 271]], [[271, 47, 46, 272]], [[45, 88, 272, 46]], [[89, 48, 51, 273]], [[273, 51, 50, 274]], [[49, 90, 274, 50]]]),
        extrude(outline(polyline([(145.0, 0.0), (145.0, -270.0), (-145.0, -270.0), (-145.0, 0.0), (145.0, 0.0)]), holes=[polyline([(-142.5, -2.5), (-142.5, -267.5), (142.5, -267.5), (142.5, -2.5), (-142.5, -2.5)])]), frame((0.0, 0.0, 85.0), z_axis=(0.0, 0.0, 1.0), x_axis=(1.0, 0.0, 0.0)), (0.0, 0.0, 1.0), 615.0),
        advanced_brep(
        [(21.104, -271.0, 123.896), (21.104, -271.0, 124.704), (26.456, -271.0, 124.704), (17.144, -271.0, 124.704), (19.344, -271.0, 122.0), (26.32, -271.0, 123.896), (23.904, -271.0, 123.896), (22.0, -271.0, 123.0), (21.104, -271.0, 125.728), (21.104, -271.0, 126.6), (22.472, -271.0, 126.6), (22.472, -271.0, 125.728), (21.104, -270.0, 123.896), (22.0, -270.0, 123.0), (23.904, -270.0, 123.896), (26.32, -270.0, 123.896), (19.344, -270.0, 122.0), (17.144, -270.0, 124.704), (26.456, -270.0, 124.704), (21.104, -270.0, 124.704), (21.104, -270.0, 125.728), (22.472, -270.0, 125.728), (22.472, -270.0, 126.6), (21.104, -270.0, 126.6)],
        [
            (0, 1),
            (1, 2),
            (2, 3, ellipse_curve(frame((21.8, -271.0, 124.704), z_axis=(0.0, -1.0, -1.2192856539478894e-11), x_axis=(-1.0, 0.0, 0.0)), 4.656, 3.848)),
            (3, 4, circle_curve(frame((20.2400436, -271.0, 124.976), z_axis=(0.0, -1.0, -1.2192856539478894e-11), x_axis=(0.0, 1.2192856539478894e-11, -1.0)), 3.1079688)),
            (4, 5, circle_curve(frame((21.7067936, -271.0, 127.088), z_axis=(0.0, -1.0, -1.2192856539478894e-11), x_axis=(0.0, 1.2192856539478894e-11, -1.0)), 5.6098607)),
            (5, 6),
            (6, 7, circle_curve(frame((22.3910588, -271.0, 124.64), z_axis=(0.0, 1.0, 1.2192856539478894e-11), x_axis=(0.0, 1.2192856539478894e-11, -1.0)), 1.6859795)),
            (7, 0, circle_curve(frame((22.0, -271.0, 123.896), z_axis=(0.0, 1.0, 1.2192856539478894e-11), x_axis=(0.0, 1.2192856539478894e-11, -1.0)), 0.896)),
            (8, 9),
            (9, 10, circle_curve(frame((21.788, -271.0, 126.6), z_axis=(0.0, 1.0, 1.2192856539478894e-11), x_axis=(0.0, 1.2192856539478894e-11, -1.0)), 0.684)),
            (10, 11),
            (11, 8),
            (12, 13, circle_curve(frame((22.0, -270.0, 123.896), z_axis=(0.0, -1.0, -1.2192856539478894e-11), x_axis=(0.0, 1.2192856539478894e-11, -1.0)), 0.896)),
            (13, 14, circle_curve(frame((22.3910588, -270.0, 124.64), z_axis=(0.0, -1.0, -1.2192856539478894e-11), x_axis=(0.0, 1.2192856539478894e-11, -1.0)), 1.6859795)),
            (14, 15),
            (15, 16, circle_curve(frame((21.7067936, -270.0, 127.088), z_axis=(0.0, 1.0, 1.2192856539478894e-11), x_axis=(0.0, 1.2192856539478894e-11, -1.0)), 5.6098607)),
            (16, 17, circle_curve(frame((20.2400436, -270.0, 124.976), z_axis=(0.0, 1.0, 1.2192856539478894e-11), x_axis=(0.0, 1.2192856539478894e-11, -1.0)), 3.1079688)),
            (17, 18, ellipse_curve(frame((21.8, -270.0, 124.704), z_axis=(0.0, 1.0, 1.2192856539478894e-11), x_axis=(-1.0, 0.0, 0.0)), 4.656, 3.848)),
            (18, 19),
            (19, 12),
            (20, 21),
            (21, 22),
            (22, 23, circle_curve(frame((21.788, -270.0, 126.6), z_axis=(0.0, -1.0, -1.2192856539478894e-11), x_axis=(0.0, 1.2192856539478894e-11, -1.0)), 0.684)),
            (23, 20),
            (0, 12),
            (19, 1),
            (18, 2),
            (5, 15),
            (14, 6),
            (17, 3),
            (13, 7),
            (16, 4),
            (8, 20),
            (23, 9),
            (22, 10),
            (21, 11),
        ],
        [
            plane_surface(frame((21.104, -271.0, 124.704), z_axis=(0.0, -1.0, -1.2192856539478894e-11), x_axis=(0.0, -1.2192856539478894e-11, 1.0))),
            plane_surface(frame((21.104, -270.0, 124.704), z_axis=(0.0, 1.0, 1.2192856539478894e-11), x_axis=(0.0, 1.2192856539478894e-11, -1.0))),
            plane_surface(frame((21.104, -271.0, 123.896), z_axis=(1.0, 0.0, 0.0), x_axis=(0.0, 1.0, 1.2192856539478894e-11))),
            plane_surface(frame((21.104, -271.0, 124.704), z_axis=(0.0, 1.2192856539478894e-11, -1.0), x_axis=(0.0, 1.0, 1.2192856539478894e-11))),
            plane_surface(frame((26.32, -271.0, 123.896), z_axis=(0.0, -1.2192856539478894e-11, 1.0), x_axis=(0.0, 1.0, 1.2192856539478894e-11))),
            extruded_surface(trimmed(ellipse_curve(frame((21.8, -269.0, 124.704), z_axis=(0.0, -1.0, -1.2192856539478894e-11), x_axis=(-1.0, 0.0, 0.0)), 4.656, 3.848), [point((26.456, -269.0, 124.704))], [point((17.144, -269.0, 124.704))], True, "CARTESIAN"), (0.0, -1.0, 0.0), 1.0),
            revolved_surface(polyline([(22.3910588, -269.9999999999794, 122.9540205), (22.3910588, -270.99999999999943, 122.9540204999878)]), (22.3910588, -270.0, 124.64), (0.0, 1.0, 1.2192856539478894e-11)),
            revolved_surface(polyline([(22.0, -269.9999999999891, 123.0), (22.0, -271.0, 122.9999999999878)]), (22.0, -270.0, 123.896), (0.0, 1.0, 1.2192856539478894e-11)),
            cylinder_surface(frame((20.2400436, -270.0, 124.976), z_axis=(0.0, -1.0, -1.2192856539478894e-11), x_axis=(0.0, 1.2192856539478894e-11, -1.0)), 3.1079688),
            cylinder_surface(frame((21.7067936, -270.0, 127.088), z_axis=(0.0, -1.0, -1.2192856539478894e-11), x_axis=(0.0, 1.2192856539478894e-11, -1.0)), 5.6098607),
            plane_surface(frame((21.104, -271.0, 125.728), z_axis=(1.0, 0.0, 0.0), x_axis=(0.0, 1.0, 1.2192856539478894e-11))),
            revolved_surface(polyline([(21.788, -269.99999999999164, 125.916), (21.788, -270.99999999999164, 125.9159999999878)]), (21.788, -270.0, 126.6), (0.0, 1.0, 1.2192856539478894e-11)),
            plane_surface(frame((22.472, -271.0, 126.6), z_axis=(-1.0, 0.0, 0.0), x_axis=(0.0, 1.0, 1.2192856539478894e-11))),
            plane_surface(frame((22.472, -271.0, 125.728), z_axis=(0.0, -1.2192856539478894e-11, 1.0), x_axis=(0.0, 1.0, 1.2192856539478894e-11))),
        ],
        [
            (0, [[1, 2, 3, 4, 5, 6, 7, 8], [9, 10, 11, 12]]),
            (1, [[13, 14, 15, 16, 17, 18, 19, 20], [21, 22, 23, 24]]),
            (2, [[-1, 25, -20, 26]]),
            (3, [[-2, -26, -19, 27]]),
            (4, [[-6, 28, -15, 29]]),
            (5, [[-3, -27, -18, 30]]),
            (6, [[-7, -29, -14, 31]]),
            (7, [[-8, -31, -13, -25]]),
            (8, [[-4, -30, -17, 32]]),
            (9, [[-5, -32, -16, -28]]),
            (10, [[-9, 33, -24, 34]]),
            (11, [[-10, -34, -23, 35]]),
            (12, [[-11, -35, -22, 36]]),
            (13, [[-12, -36, -21, -33]]),
        ],
    ),
        advanced_brep(
        [(4.408, -271.0, 123.896), (4.408, -271.0, 124.704), (9.76, -271.0, 124.704), (0.448, -271.0, 124.704), (2.648, -271.0, 122.0), (9.624, -271.0, 123.896), (7.208, -271.0, 123.896), (5.304, -271.0, 123.0), (4.408, -271.0, 125.728), (4.408, -271.0, 126.6), (5.776, -271.0, 126.6), (5.776, -271.0, 125.728), (4.408, -270.0, 123.896), (5.304, -270.0, 123.0), (7.208, -270.0, 123.896), (9.624, -270.0, 123.896), (2.648, -270.0, 122.0), (0.448, -270.0, 124.704), (9.76, -270.0, 124.704), (4.408, -270.0, 124.704), (4.408, -270.0, 125.728), (5.776, -270.0, 125.728), (5.776, -270.0, 126.6), (4.408, -270.0, 126.6)],
        [
            (0, 1),
            (1, 2),
            (2, 3, ellipse_curve(frame((5.104, -271.0, 124.704), z_axis=(0.0, -1.0, -1.2192856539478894e-11), x_axis=(-1.0, 0.0, 0.0)), 4.656, 3.848)),
            (3, 4, circle_curve(frame((3.5440436, -271.0, 124.976), z_axis=(0.0, -1.0, -1.2192856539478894e-11), x_axis=(0.0, 1.2192856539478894e-11, -1.0)), 3.1079688)),
            (4, 5, circle_curve(frame((5.0107936, -271.0, 127.088), z_axis=(0.0, -1.0, -1.2192856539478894e-11), x_axis=(0.0, 1.2192856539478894e-11, -1.0)), 5.6098607)),
            (5, 6),
            (6, 7, circle_curve(frame((5.6950588, -271.0, 124.64), z_axis=(0.0, 1.0, 1.2192856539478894e-11), x_axis=(0.0, 1.2192856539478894e-11, -1.0)), 1.6859795)),
            (7, 0, circle_curve(frame((5.304, -271.0, 123.896), z_axis=(0.0, 1.0, 1.2192856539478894e-11), x_axis=(0.0, 1.2192856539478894e-11, -1.0)), 0.896)),
            (8, 9),
            (9, 10, circle_curve(frame((5.092, -271.0, 126.6), z_axis=(0.0, 1.0, 1.2192856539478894e-11), x_axis=(0.0, 1.2192856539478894e-11, -1.0)), 0.684)),
            (10, 11),
            (11, 8),
            (12, 13, circle_curve(frame((5.304, -270.0, 123.896), z_axis=(0.0, -1.0, -1.2192856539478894e-11), x_axis=(0.0, 1.2192856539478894e-11, -1.0)), 0.896)),
            (13, 14, circle_curve(frame((5.6950588, -270.0, 124.64), z_axis=(0.0, -1.0, -1.2192856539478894e-11), x_axis=(0.0, 1.2192856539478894e-11, -1.0)), 1.6859795)),
            (14, 15),
            (15, 16, circle_curve(frame((5.0107936, -270.0, 127.088), z_axis=(0.0, 1.0, 1.2192856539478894e-11), x_axis=(0.0, 1.2192856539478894e-11, -1.0)), 5.6098607)),
            (16, 17, circle_curve(frame((3.5440436, -270.0, 124.976), z_axis=(0.0, 1.0, 1.2192856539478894e-11), x_axis=(0.0, 1.2192856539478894e-11, -1.0)), 3.1079688)),
            (17, 18, ellipse_curve(frame((5.104, -270.0, 124.704), z_axis=(0.0, 1.0, 1.2192856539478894e-11), x_axis=(-1.0, 0.0, 0.0)), 4.656, 3.848)),
            (18, 19),
            (19, 12),
            (20, 21),
            (21, 22),
            (22, 23, circle_curve(frame((5.092, -270.0, 126.6), z_axis=(0.0, -1.0, -1.2192856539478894e-11), x_axis=(0.0, 1.2192856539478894e-11, -1.0)), 0.684)),
            (23, 20),
            (0, 12),
            (19, 1),
            (18, 2),
            (5, 15),
            (14, 6),
            (17, 3),
            (13, 7),
            (16, 4),
            (8, 20),
            (23, 9),
            (22, 10),
            (21, 11),
        ],
        [
            plane_surface(frame((4.408, -271.0, 124.704), z_axis=(0.0, -1.0, -1.2192856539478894e-11), x_axis=(0.0, -1.2192856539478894e-11, 1.0))),
            plane_surface(frame((4.408, -270.0, 124.704), z_axis=(0.0, 1.0, 1.2192856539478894e-11), x_axis=(0.0, 1.2192856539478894e-11, -1.0))),
            plane_surface(frame((4.408, -271.0, 123.896), z_axis=(1.0, 0.0, 0.0), x_axis=(0.0, 1.0, 1.2192856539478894e-11))),
            plane_surface(frame((4.408, -271.0, 124.704), z_axis=(0.0, 1.2192856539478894e-11, -1.0), x_axis=(0.0, 1.0, 1.2192856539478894e-11))),
            plane_surface(frame((9.624, -271.0, 123.896), z_axis=(0.0, -1.2192856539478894e-11, 1.0), x_axis=(0.0, 1.0, 1.2192856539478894e-11))),
            extruded_surface(trimmed(ellipse_curve(frame((5.104, -269.0, 124.704), z_axis=(0.0, -1.0, -1.2192856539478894e-11), x_axis=(-1.0, 0.0, 0.0)), 4.656, 3.848), [point((9.76, -269.0, 124.704))], [point((0.448, -269.0, 124.704))], True, "CARTESIAN"), (0.0, -1.0, 0.0), 1.0),
            revolved_surface(polyline([(5.6950588, -269.9999999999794, 122.9540205), (5.6950588, -270.99999999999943, 122.9540204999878)]), (5.6950588, -270.0, 124.64), (0.0, 1.0, 1.2192856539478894e-11)),
            revolved_surface(polyline([(5.304, -269.9999999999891, 123.0), (5.304, -271.0, 122.9999999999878)]), (5.304, -270.0, 123.896), (0.0, 1.0, 1.2192856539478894e-11)),
            cylinder_surface(frame((3.5440436, -270.0, 124.976), z_axis=(0.0, -1.0, -1.2192856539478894e-11), x_axis=(0.0, 1.2192856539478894e-11, -1.0)), 3.1079688),
            cylinder_surface(frame((5.0107936, -270.0, 127.088), z_axis=(0.0, -1.0, -1.2192856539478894e-11), x_axis=(0.0, 1.2192856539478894e-11, -1.0)), 5.6098607),
            plane_surface(frame((4.408, -271.0, 125.728), z_axis=(1.0, 0.0, 0.0), x_axis=(0.0, 1.0, 1.2192856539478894e-11))),
            revolved_surface(polyline([(5.092, -269.99999999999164, 125.916), (5.092, -270.99999999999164, 125.9159999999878)]), (5.092, -270.0, 126.6), (0.0, 1.0, 1.2192856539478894e-11)),
            plane_surface(frame((5.776, -271.0, 126.6), z_axis=(-1.0, 0.0, 0.0), x_axis=(0.0, 1.0, 1.2192856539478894e-11))),
            plane_surface(frame((5.776, -271.0, 125.728), z_axis=(0.0, -1.2192856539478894e-11, 1.0), x_axis=(0.0, 1.0, 1.2192856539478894e-11))),
        ],
        [
            (0, [[1, 2, 3, 4, 5, 6, 7, 8], [9, 10, 11, 12]]),
            (1, [[13, 14, 15, 16, 17, 18, 19, 20], [21, 22, 23, 24]]),
            (2, [[-1, 25, -20, 26]]),
            (3, [[-2, -26, -19, 27]]),
            (4, [[-6, 28, -15, 29]]),
            (5, [[-3, -27, -18, 30]]),
            (6, [[-7, -29, -14, 31]]),
            (7, [[-8, -31, -13, -25]]),
            (8, [[-4, -30, -17, 32]]),
            (9, [[-5, -32, -16, -28]]),
            (10, [[-9, 33, -24, 34]]),
            (11, [[-10, -34, -23, 35]]),
            (12, [[-11, -35, -22, 36]]),
            (13, [[-12, -36, -21, -33]]),
        ],
    ),
        extrude(outline(polyline([(0.0, 0.0), (1.4315306, 0.0), (1.4390415, -2.9920868), (0.0109086, -2.9993294), (0.0, 0.0)])), frame((-4.336, -271.0, 129.528), z_axis=(0.0, 1.0, 1.2192856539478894e-11), x_axis=(0.42472021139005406, 1.1041186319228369e-11, -0.9053246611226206)), (0.0, 0.0, 1.0), 1.0),
        extrude(outline(polyline([(0.4933908, 2.4141097), (1.7898157, 3.022309), (2.1941493, 2.1604399), (5.1636142, 3.5535222), (4.7592806, 4.4153913), (5.9760369, 4.9862153), (8.6568709, -0.728194), (7.4401145, -1.2990179), (7.0459742, -0.4588767), (2.7800844, -2.4601583), (0.4933908, 2.4141097)])), frame((-4.336, -271.0, 129.528), z_axis=(0.0, 1.0, 1.2192856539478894e-11), x_axis=(0.42472021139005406, 1.1041186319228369e-11, -0.9053246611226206)), (0.0, 0.0, 1.0), 1.0),
        extrude(outline(polyline([(0.0, 0.0), (0.96, 0.0), (0.96, 5.352), (0.0, 5.352), (0.0, 6.696), (6.488, 6.696), (6.488, 5.352), (5.504, 5.352), (5.504, -1.304), (0.0, -1.304), (0.0, 0.0)])), frame((10.208, -271.0, 128.696), z_axis=(0.0, 1.0, 1.2192856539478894e-11), x_axis=(1.0, 0.0, 0.0)), (0.0, 0.0, 1.0), 1.0),
        extrude(outline(polyline([(0.0, 0.0), (0.968, 0.0), (0.968, 5.352), (0.0, 5.352), (0.0, 6.696), (3.52, 6.696), (3.52, 5.352), (2.56, 5.352), (2.56, 1.9488753), (6.136, 6.696), (9.728, 1.8807777), (9.728, 5.352), (8.744, 5.352), (8.744, 6.696), (15.128, 6.696), (15.128, 5.352), (14.112, 5.352), (14.112, 0.0), (15.128, 0.0), (15.128, -1.304), (10.256, -1.304), (7.92, 1.696), (5.576, -1.304), (0.0, -1.304), (0.0, 0.0)])), frame((-22.256, -271.0, 128.696), z_axis=(0.0, 1.0, 1.2192856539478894e-11), x_axis=(1.0, 0.0, 0.0)), (0.0, 0.0, 1.0), 1.0),
        extrude(outline(polyline([(78.0, -500.0), (78.0, -501.0), (-78.0, -501.0), (-78.0, -500.0), (78.0, -500.0)])), frame((0.0, 0.0, 27.0), z_axis=(0.0, 0.0, 1.0), x_axis=(1.0, 0.0, 0.0)), (0.0, 0.0, 1.0), 8.0),
        faceted_brep([(449.0, 0.0, 85.0), (-449.0, 0.0, 85.0), (-449.0, -500.0, 85.0), (449.0, -500.0, 85.0), (449.0, 0.0, 0.0), (449.0, -500.0, 0.0), (-449.0, -500.0, 0.0), (-449.0, 0.0, 0.0), (-422.0, 0.0, 0.0), (-422.0, -473.0, 0.0), (422.0, -473.0, 0.0), (422.0, 0.0, 0.0), (422.0, 0.0, 2.0), (-422.0, 0.0, 2.0), (422.0, -473.0, 13.7), (422.0, -97.0, 13.7), (422.0, -97.0, 2.0), (422.0, -94.2, 2.0), (422.0, -78.2, 18.0), (422.0, -18.5, 2.0), (-422.0, -473.0, 13.7), (-422.0, -18.5, 2.0), (-422.0, -78.2, 18.0), (-422.0, -94.2, 2.0), (-422.0, -97.0, 2.0), (-422.0, -97.0, 13.7)], [[[0, 1, 2, 3]], [[4, 5, 6, 7, 8, 9, 10, 11]], [[1, 0, 4, 11, 12, 13, 8, 7]], [[2, 1, 7, 6]], [[3, 2, 6, 5]], [[0, 3, 5, 4]], [[14, 15, 16, 17, 18, 19, 12, 11, 10]], [[20, 9, 8, 13, 21, 22, 23, 24, 25]], [[14, 10, 9, 20]], [[12, 19, 21, 13]], [[19, 18, 22, 21]], [[18, 17, 23, 22]], [[17, 16, 24, 23]], [[16, 15, 25, 24]], [[15, 14, 20, 25]]]),
        extrude(outline(polyline([(-8.547125, -112.7), (-4.5372113, -102.654369), (-3.4679009, -102.654369), (0.5420128, -112.7), (-0.7848149, -112.7), (-1.9350593, -109.5607403), (-6.0725055, -109.5607403), (-7.2202973, -112.7), (-8.547125, -112.7)]), holes=[polyline([(-5.6114267, -108.3050364), (-2.3936855, -108.3050364), (-3.2986752, -105.835322), (-4.0025561, -103.9100729), (-4.6279555, -105.6194979), (-5.6114267, -108.3050364)])]), frame((0.0, 0.0, 462.0), z_axis=(0.0, 0.0, 1.0), x_axis=(1.0, 0.0, 0.0)), (0.0, 0.0, 1.0), 1.0),
        extrude(outline(polyline([(1.8835558, -112.7), (1.8835558, -102.654369), (3.1392597, -102.654369), (3.1392597, -111.4442961), (8.1620752, -111.4442961), (8.1620752, -112.7), (1.8835558, -112.7)])), frame((0.0, 0.0, 462.0), z_axis=(0.0, 0.0, 1.0), x_axis=(1.0, 0.0, 0.0)), (0.0, 0.0, 1.0), 1.0),
        extrude(outline(polyline([(407.8, 95.1164442), (417.845631, 95.1164442), (417.845631, 93.8607403), (409.0557039, 93.8607403), (409.0557039, 88.8379248), (407.8, 88.8379248), (407.8, 95.1164442)])), frame((0.0, -164.0, 0.0), z_axis=(0.0, 1.0, 0.0), x_axis=(0.0, 0.0, 1.0)), (0.0, 0.0, 1.0), 1.0),
        extrude(outline(polyline([(407.8, 104.3772603), (417.845631, 104.3772603), (417.845631, 97.156963), (416.5899271, 97.156963), (416.5899271, 103.1215564), (413.6076304, 103.1215564), (413.6076304, 97.470889), (412.3519266, 97.470889), (412.3519266, 103.1215564), (409.0557039, 103.1215564), (409.0557039, 97.0), (407.8, 97.0), (407.8, 104.3772603)])), frame((0.0, -164.0, 0.0), z_axis=(0.0, 1.0, 0.0), x_axis=(0.0, 0.0, 1.0)), (0.0, 0.0, 1.0), 1.0),
        extrude(outline(composite_curve([segment(trimmed(circle_curve(frame_2d((412.8, 97.0)), 7.5369395), [point((412.8, 104.5369395))], [point((412.8, 89.4630605))], False, "CARTESIAN"), True, "CONTINUOUS"), segment(trimmed(circle_curve(frame_2d((412.8, 97.0)), 7.5369395), [point((412.8, 89.4630605))], [point((412.8, 104.5369395))], False, "CARTESIAN"), True, "CONTINUOUS")], self_intersect=False)), frame((0.0, -194.0, 0.0), z_axis=(0.0, 1.0, 0.0), x_axis=(0.0, 0.0, 1.0)), (0.0, 0.0, 1.0), 30.0),
        extrude(outline(polyline([(124.5, -263.0), (-123.0, -263.0), (-123.0, -194.0), (124.5, -194.0), (124.5, -263.0)])), frame((0.0, 0.0, 402.8), z_axis=(0.0, 0.0, 1.0), x_axis=(1.0, 0.0, 0.0)), (0.0, 0.0, 1.0), 120.2),
        extrude(outline(composite_curve([segment(trimmed(circle_curve(frame_2d((0.0, -107.7)), 75.0), [point((-75.0, -107.7))], [point((75.0, -107.7))], False, "CARTESIAN"), True, "CONTINUOUS"), segment(trimmed(circle_curve(frame_2d((0.0, -107.7)), 75.0), [point((75.0, -107.7))], [point((-75.0, -107.7))], False, "CARTESIAN"), True, "CONTINUOUS")], self_intersect=False), holes=[composite_curve([segment(trimmed(circle_curve(frame_2d((0.0, -107.7)), 72.5), [point((-72.5, -107.7))], [point((72.5, -107.7))], True, "CARTESIAN"), True, "CONTINUOUS"), segment(trimmed(circle_curve(frame_2d((0.0, -107.7)), 72.5), [point((72.5, -107.7))], [point((-72.5, -107.7))], True, "CARTESIAN"), True, "CONTINUOUS")], self_intersect=False)]), frame((0.0, 0.0, 402.8), z_axis=(0.0, 0.0, 1.0), x_axis=(1.0, 0.0, 0.0)), (0.0, 0.0, 1.0), 59.2),
        extrude(outline(polyline([(141.25, -4.0), (141.25, -264.5), (-141.25, -264.5), (-141.25, -4.0), (141.25, -4.0)])), frame((0.0, 0.0, 108.7), z_axis=(0.0, 0.0, 1.0), x_axis=(1.0, 0.0, 0.0)), (0.0, 0.0, 1.0), 294.1),
        extrude(outline(polyline([(142.2, -4.0), (142.2, -267.0), (-142.2, -267.0), (-142.2, -4.0), (142.2, -4.0)])), frame((0.0, 0.0, 85.0), z_axis=(0.0, 0.0, 1.0), x_axis=(1.0, 0.0, 0.0)), (0.0, 0.0, 1.0), 23.7),
    ])


if __name__ == "__main__":
    model = new_model("IFC4")
    model_context = context("Model", 3, world=origin())
    ifc_project = project(units=[si_unit("LENGTHUNIT", "METRE", prefix="MILLI")], contexts=[model_context])
    site = spatial("IfcSite", under=ifc_project)
    building = spatial("IfcBuilding", under=site)
    placement = place(None, origin())
    specialty_equipment_shape = specialty_equipment_d0c3b859(model_context)
    element("IfcBuildingElementProxy", 1, Name="Specialty Equipment", at=placement, inside=building, context=model_context, shape_type="MappedRepresentation", body=[
        mapped(specialty_equipment_shape, transform((0.0, 0.0, 0.0), x_axis=(1.0, 0.0, 0.0), y_axis=(0.0, 1.0, 0.0), z_axis=(0.0, 0.0, 1.0))),
    ])
    save(model, "model.ifc")
